VERSION 5.7 ;
  NOWIREEXTENSIONATPIN ON ;
  DIVIDERCHAR "/" ;
  BUSBITCHARS "[]" ;
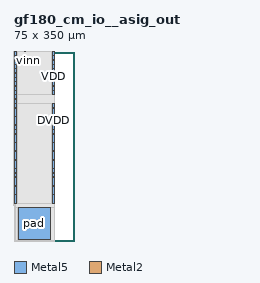
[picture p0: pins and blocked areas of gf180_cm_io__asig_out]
MACRO gf180_cm_io__asig_out
  CLASS PAD INOUT ;
  FOREIGN gf180_cm_io__asig_out ;
  ORIGIN 0.000 0.000 ;
  SIZE 75.000 BY 350.000 ;
  SYMMETRY X Y R90 ;
  SITE GF_IO_Site ;
  PIN pad
    DIRECTION INOUT ;
    USE SIGNAL ;
    ANTENNADIFFAREA 335.279999 ;
    PORT
      LAYER Metal5 ;
        RECT 7.500 2.000 67.500 62.000 ;
    END
  END pad
  PIN DVDD
    DIRECTION INOUT ;
    USE POWER ;
    PORT
      LAYER Metal5 ;
        RECT 70.000 334.000 75.000 341.000 ;
    END
    PORT
      LAYER Metal5 ;
        RECT 70.000 294.000 75.000 301.000 ;
    END
    PORT
      LAYER Metal5 ;
        RECT 70.000 278.000 75.000 285.000 ;
    END
    PORT
      LAYER Metal5 ;
        RECT 70.000 270.000 75.000 277.000 ;
    END
    PORT
      LAYER Metal5 ;
        RECT 70.000 214.000 75.000 229.000 ;
    END
    PORT
      LAYER Metal5 ;
        RECT 70.000 206.000 75.000 213.000 ;
    END
    PORT
      LAYER Metal5 ;
        RECT 70.000 182.000 75.000 197.000 ;
    END
    PORT
      LAYER Metal5 ;
        RECT 70.000 166.000 75.000 181.000 ;
    END
    PORT
      LAYER Metal5 ;
        RECT 70.000 150.000 75.000 165.000 ;
    END
    PORT
      LAYER Metal5 ;
        RECT 70.000 134.000 75.000 149.000 ;
    END
    PORT
      LAYER Metal5 ;
        RECT 70.000 118.000 75.000 125.000 ;
    END
    PORT
      LAYER Metal5 ;
        RECT 0.000 334.000 5.000 341.000 ;
    END
    PORT
      LAYER Metal5 ;
        RECT 0.000 294.000 5.000 301.000 ;
    END
    PORT
      LAYER Metal5 ;
        RECT 0.000 278.000 5.000 285.000 ;
    END
    PORT
      LAYER Metal5 ;
        RECT 0.000 270.000 5.000 277.000 ;
    END
    PORT
      LAYER Metal5 ;
        RECT 0.000 262.000 5.000 269.000 ;
    END
    PORT
      LAYER Metal5 ;
        RECT 0.000 214.000 5.000 229.000 ;
    END
    PORT
      LAYER Metal5 ;
        RECT 0.000 206.000 5.000 213.000 ;
    END
    PORT
      LAYER Metal5 ;
        RECT 0.000 182.000 5.000 197.000 ;
    END
    PORT
      LAYER Metal5 ;
        RECT 0.000 166.000 5.000 181.000 ;
    END
    PORT
      LAYER Metal5 ;
        RECT 0.000 150.000 5.000 165.000 ;
    END
    PORT
      LAYER Metal5 ;
        RECT 0.000 134.000 5.000 149.000 ;
    END
    PORT
      LAYER Metal5 ;
        RECT 0.000 118.000 5.000 125.000 ;
    END
  END DVDD
  PIN DVSS
    DIRECTION INOUT ;
    USE GROUND ;
    PORT
      LAYER Metal5 ;
        RECT 70.000 342.000 75.000 348.390 ;
    END
    PORT
      LAYER Metal5 ;
        RECT 70.000 326.000 75.000 333.000 ;
    END
    PORT
      LAYER Metal5 ;
        RECT 70.000 302.000 75.000 309.000 ;
    END
    PORT
      LAYER Metal5 ;
        RECT 70.000 286.000 75.000 293.000 ;
    END
    PORT
      LAYER Metal5 ;
        RECT 70.000 230.000 75.000 245.000 ;
    END
    PORT
      LAYER Metal5 ;
        RECT 70.000 198.000 75.000 205.000 ;
    END
    PORT
      LAYER Metal5 ;
        RECT 70.000 126.000 75.000 133.000 ;
    END
    PORT
      LAYER Metal5 ;
        RECT 70.000 102.000 75.000 117.000 ;
    END
    PORT
      LAYER Metal5 ;
        RECT 70.000 86.000 75.000 101.000 ;
    END
    PORT
      LAYER Metal5 ;
        RECT 70.000 70.000 75.000 85.000 ;
    END
    PORT
      LAYER Metal5 ;
        RECT 0.000 342.000 5.000 348.390 ;
    END
    PORT
      LAYER Metal5 ;
        RECT 0.000 326.000 5.000 333.000 ;
    END
    PORT
      LAYER Metal5 ;
        RECT 0.000 302.000 5.000 309.000 ;
    END
    PORT
      LAYER Metal5 ;
        RECT 0.000 286.000 5.000 293.000 ;
    END
    PORT
      LAYER Metal5 ;
        RECT 0.000 230.000 5.000 245.000 ;
    END
    PORT
      LAYER Metal5 ;
        RECT 0.000 198.000 5.000 205.000 ;
    END
    PORT
      LAYER Metal5 ;
        RECT 0.000 126.000 5.000 133.000 ;
    END
    PORT
      LAYER Metal5 ;
        RECT 0.000 102.000 5.000 117.000 ;
    END
    PORT
      LAYER Metal5 ;
        RECT 0.000 86.000 5.000 101.000 ;
    END
    PORT
      LAYER Metal5 ;
        RECT 0.000 70.000 5.000 85.000 ;
    END
  END DVSS
  PIN VDD
    DIRECTION INOUT ;
    USE POWER ;
    PORT
      LAYER Metal5 ;
        RECT 70.000 310.000 75.000 317.000 ;
    END
    PORT
      LAYER Metal5 ;
        RECT 0.000 310.000 5.000 317.000 ;
    END
    PORT
      LAYER Metal5 ;
        RECT 0.000 254.000 5.000 261.000 ;
    END
  END VDD
  PIN VSS
    DIRECTION INOUT ;
    USE GROUND ;
    PORT
      LAYER Metal5 ;
        RECT 70.000 318.000 75.000 325.000 ;
    END
    PORT
      LAYER Metal5 ;
        RECT 70.000 246.000 75.000 253.000 ;
    END
    PORT
      LAYER Metal5 ;
        RECT 0.000 318.000 5.000 325.000 ;
    END
    PORT
      LAYER Metal5 ;
        RECT 0.000 246.000 5.000 253.000 ;
    END
  END VSS
  PIN vinp
    DIRECTION INPUT ;
    USE SIGNAL ;
    PORT
      LAYER Metal2 ;
        RECT 20.000 348.400 20.380 350.000 ;
    END
  END vinp
  PIN vinn
    DIRECTION INPUT ;
    USE SIGNAL ;
    PORT
      LAYER Metal2 ;
        RECT 25.000 348.400 25.380 350.000 ;
    END
  END vinn
  PIN vref
    DIRECTION INPUT ;
    USE SIGNAL ;
    PORT
      LAYER Metal2 ;
        RECT 30.000 348.400 30.380 350.000 ;
    END
  END vref
  PIN iref
    DIRECTION INOUT ;
    USE SIGNAL ;
    PORT
      LAYER Metal2 ;
        RECT 35.000 348.400 35.380 350.000 ;
    END
  END iref
  PIN en_3v3
    DIRECTION INPUT ;
    USE SIGNAL ;
    PORT
      LAYER Metal2 ;
        RECT 40.000 348.400 40.380 350.000 ;
    END
  END en_3v3
  PIN en_3v3_b
    DIRECTION INPUT ;
    USE SIGNAL ;
    PORT
      LAYER Metal2 ;
        RECT 45.000 348.400 45.380 350.000 ;
    END
  END en_3v3_b
  OBS
      LAYER Nwell ;
        RECT 1.805 67.400 73.195 346.295 ;
      LAYER Metal1 ;
        RECT -0.160 65.540 75.160 349.785 ;
      LAYER Metal2 ;
        RECT 0.000 348.100 19.700 349.760 ;
        RECT 20.680 348.100 24.700 349.760 ;
        RECT 25.680 348.100 29.700 349.760 ;
        RECT 30.680 348.100 34.700 349.760 ;
        RECT 35.680 348.100 39.700 349.760 ;
        RECT 40.680 348.100 44.700 349.760 ;
        RECT 45.680 348.100 75.000 349.760 ;
        RECT 0.000 0.000 75.000 348.100 ;
      LAYER Metal3 ;
        RECT 0.000 0.000 75.000 348.390 ;
      LAYER Metal4 ;
        RECT 0.000 0.000 75.000 348.390 ;
      LAYER Metal5 ;
        RECT 5.600 269.400 69.400 348.390 ;
        RECT 5.600 253.600 75.000 269.400 ;
        RECT 5.600 69.400 69.400 253.600 ;
        RECT 3.500 62.600 75.000 69.400 ;
        RECT 3.500 1.400 6.900 62.600 ;
        RECT 68.100 1.400 75.000 62.600 ;
        RECT 3.500 0.000 75.000 1.400 ;
  END
END gf180_cm_io__asig_out
END LIBRARY

